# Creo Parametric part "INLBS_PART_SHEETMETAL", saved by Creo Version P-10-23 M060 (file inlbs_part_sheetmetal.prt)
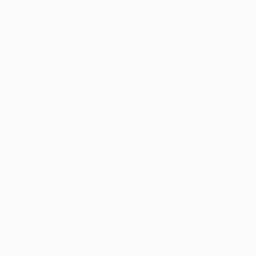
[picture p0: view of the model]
Units: Inch lbm Second (Pro/E Default); INCH, POUND, SECS

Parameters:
  SMT_PART_BEND_ALLOW_FACTOR_TYPE = "Y FACTOR"
  SMT_DFLT_RADIUS_SIDE = "Inside"
  SMT_DFLT_CRNR_REL_TYPE = "V Notch"
  SMT_DFLT_CRNR_REL_DEPTH_TYPE = "Blind"
  SMT_DFLT_BEND_REL_TYPE = "Rip"
  SMT_DFLT_BEND_REL_DEPTH_TYPE = "Up to Bend"
  SMT_DFLT_EDGE_TREA_TYPE = "Open"

Other parameters: SMT_THICKNESS, SMT_PART_BEND_ALLOWANCE_FACTOR, SMT_UPDATE_BEND_ALLOW_INFO, SMT_DFLT_BEND_RADIUS, SMT_DFLT_BEND_ANGLE, SMT_DFLT_CRNR_REL_WIDTH, SMT_DFLT_CRNR_REL_DEPTH, SMT_DFLT_BEND_REL_WIDTH, SMT_DFLT_BEND_REL_DEPTH, SMT_DFLT_BEND_REL_ANGLE, SMT_GAP, SMT_DFLT_EDGE_TREA_WIDTH, SMT_DFLT_MITER_CUT_WIDTH, SMT_DFLT_MITER_CUT_OFFSET

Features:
  1. datum plane "RIGHT"
  2. datum plane "TOP"
  3. datum plane "FRONT"
  4. coordinate system

Surfaces: 3 plane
